VERSION 5.7 ;
  NOWIREEXTENSIONATPIN ON ;
  DIVIDERCHAR "/" ;
  BUSBITCHARS "[]" ;
MACRO pfet
  CLASS BLOCK ;
  FOREIGN pfet ;
  ORIGIN 1.150 0.690 ;
  SIZE 6.890 BY 13.380 ;
  OBS
      LAYER Nwell ;
        RECT -1.150 -0.690 5.740 12.690 ;
      LAYER Metal1 ;
        RECT 0.140 12.300 0.520 12.680 ;
        RECT 0.940 12.300 1.320 12.680 ;
        RECT 1.740 12.300 2.120 12.680 ;
        RECT 2.540 12.300 2.920 12.680 ;
        RECT 3.340 12.300 3.720 12.680 ;
        RECT -0.420 0.200 -0.040 11.800 ;
        RECT 0.540 0.200 0.920 11.800 ;
        RECT 1.340 0.200 1.720 11.800 ;
        RECT 2.140 0.200 2.520 11.800 ;
        RECT 2.940 0.200 3.320 11.800 ;
        RECT 3.900 0.200 4.280 11.800 ;
        RECT 4.630 0.200 5.010 11.800 ;
  END
END pfet
MACRO nfet
  CLASS BLOCK ;
  FOREIGN nfet ;
  ORIGIN 0.420 0.670 ;
  SIZE 5.410 BY 4.970 ;
  OBS
      LAYER Metal1 ;
        RECT -0.400 0.280 -0.020 3.720 ;
        RECT 0.540 0.280 0.920 3.720 ;
        RECT 1.340 0.280 1.720 3.720 ;
        RECT 2.140 0.280 2.520 3.720 ;
        RECT 2.940 0.280 3.320 3.720 ;
        RECT 3.880 0.280 4.260 3.720 ;
        RECT 4.590 0.280 4.970 3.720 ;
        RECT 0.140 -0.670 0.520 -0.290 ;
        RECT 0.940 -0.670 1.320 -0.290 ;
        RECT 1.740 -0.670 2.120 -0.290 ;
        RECT 2.540 -0.670 2.920 -0.290 ;
        RECT 3.340 -0.670 3.720 -0.290 ;
  END
END nfet
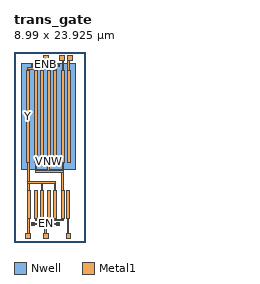
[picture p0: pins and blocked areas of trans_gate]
MACRO trans_gate
  CLASS BLOCK ;
  FOREIGN trans_gate ;
  ORIGIN 3.960 6.970 ;
  SIZE 8.990 BY 23.925 ;
  PIN VNW
    DIRECTION INOUT ;
    USE POWER ;
    PORT
      LAYER Nwell ;
        RECT -3.060 2.145 3.830 15.525 ;
      LAYER Metal1 ;
        RECT 1.760 15.900 2.360 16.500 ;
        RECT 2.750 15.900 3.350 16.500 ;
        RECT 2.090 14.635 2.290 15.900 ;
        RECT 2.810 14.635 3.010 15.900 ;
        RECT -1.370 3.035 -0.990 14.635 ;
        RECT 0.230 3.035 0.610 14.635 ;
        RECT 1.990 3.035 2.370 14.635 ;
        RECT 2.720 3.035 3.100 14.635 ;
        RECT -1.280 1.995 -1.080 3.035 ;
        RECT 0.320 1.995 0.520 3.035 ;
        RECT 2.090 1.995 2.290 3.035 ;
        RECT -1.280 1.795 2.290 1.995 ;
        RECT 2.050 -0.510 2.250 1.795 ;
        RECT -1.375 -3.950 -0.995 -0.510 ;
        RECT 0.225 -3.950 0.605 -0.510 ;
        RECT 1.965 -3.950 2.345 -0.510 ;
        RECT 2.675 -3.950 3.055 -0.510 ;
        RECT -1.290 -4.100 -1.090 -3.950 ;
        RECT 0.310 -4.100 0.510 -3.950 ;
        RECT 2.050 -4.100 2.250 -3.950 ;
        RECT -1.290 -4.300 2.250 -4.100 ;
        RECT 2.730 -5.900 2.930 -3.950 ;
        RECT 2.600 -6.500 3.200 -5.900 ;
    END
  END VNW
  PIN Y
    DIRECTION INOUT ;
    USE SIGNAL ;
    ANTENNADIFFAREA 26.879999 ;
    PORT
      LAYER Metal1 ;
        RECT -2.240 14.785 1.330 14.985 ;
        RECT -2.240 14.635 -2.040 14.785 ;
        RECT -0.475 14.635 -0.275 14.785 ;
        RECT 1.130 14.635 1.330 14.785 ;
        RECT -2.330 3.035 -1.950 14.635 ;
        RECT -0.570 3.035 -0.190 14.635 ;
        RECT 1.030 3.035 1.410 14.635 ;
        RECT -2.240 0.630 -2.040 3.035 ;
        RECT -2.240 0.430 1.280 0.630 ;
        RECT -2.240 -0.510 -2.040 0.430 ;
        RECT -0.520 -0.510 -0.320 0.430 ;
        RECT 1.080 -0.510 1.280 0.430 ;
        RECT -2.315 -3.950 -1.935 -0.510 ;
        RECT -0.575 -3.950 -0.195 -0.510 ;
        RECT 1.025 -3.950 1.405 -0.510 ;
        RECT -2.215 -5.900 -2.015 -3.950 ;
        RECT -2.530 -6.500 -1.930 -5.900 ;
    END
  END Y
  PIN ENB
    DIRECTION INPUT ;
    USE SIGNAL ;
    ANTENNAGATEAREA 16.799999 ;
    PORT
      LAYER Metal1 ;
        RECT -0.270 15.900 0.330 16.500 ;
        RECT -0.080 15.515 0.120 15.900 ;
        RECT -1.770 15.420 -1.390 15.515 ;
        RECT -0.970 15.420 -0.590 15.515 ;
        RECT -0.170 15.420 0.210 15.515 ;
        RECT 0.630 15.420 1.010 15.515 ;
        RECT 1.430 15.420 1.810 15.515 ;
        RECT -1.770 15.220 1.810 15.420 ;
        RECT -1.770 15.135 -1.390 15.220 ;
        RECT -0.970 15.135 -0.590 15.220 ;
        RECT -0.170 15.135 0.210 15.220 ;
        RECT 0.630 15.135 1.010 15.220 ;
        RECT 1.430 15.135 1.810 15.220 ;
    END
  END ENB
  PIN EN
    DIRECTION INPUT ;
    USE SIGNAL ;
    ANTENNAGATEAREA 5.600000 ;
    PORT
      LAYER Metal1 ;
        RECT -1.775 -4.595 -1.395 -4.520 ;
        RECT -0.975 -4.595 -0.595 -4.520 ;
        RECT -0.175 -4.595 0.205 -4.520 ;
        RECT 0.625 -4.595 1.005 -4.520 ;
        RECT 1.425 -4.595 1.805 -4.520 ;
        RECT -1.775 -4.795 1.805 -4.595 ;
        RECT -1.775 -4.900 -1.395 -4.795 ;
        RECT -0.975 -4.900 -0.595 -4.795 ;
        RECT -0.175 -4.900 0.205 -4.795 ;
        RECT 0.625 -4.900 1.005 -4.795 ;
        RECT 1.425 -4.900 1.805 -4.795 ;
        RECT -0.085 -5.900 0.115 -4.900 ;
        RECT -0.240 -6.500 0.360 -5.900 ;
    END
  END EN
END trans_gate
END LIBRARY

